VERSION 5.7 ;
  NOWIREEXTENSIONATPIN ON ;
  DIVIDERCHAR "/" ;
  BUSBITCHARS "[]" ;
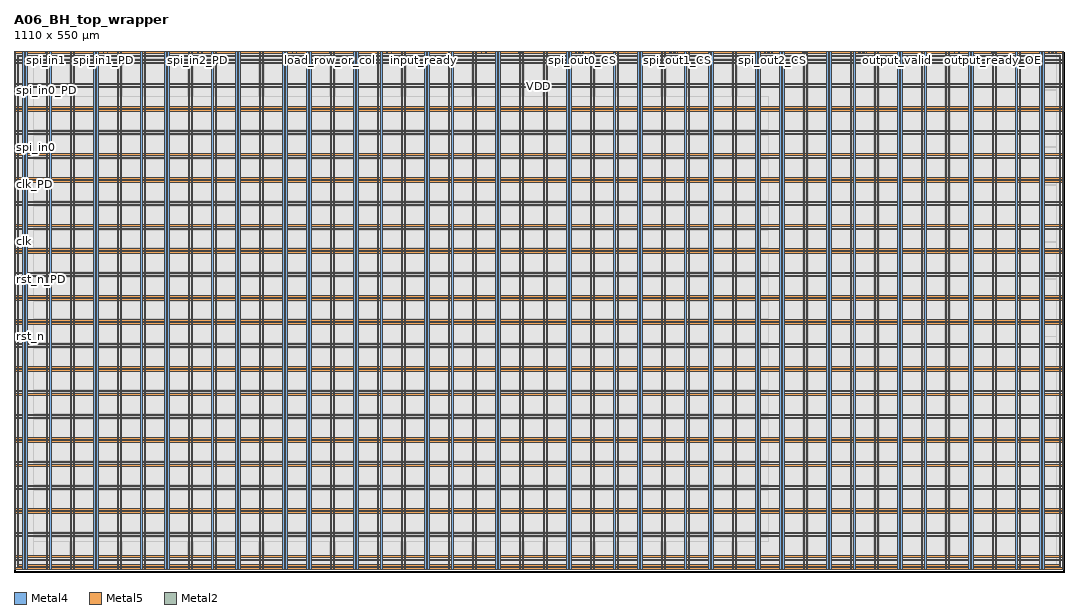
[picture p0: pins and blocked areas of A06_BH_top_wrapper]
MACRO A06_BH_top_wrapper
  CLASS BLOCK ;
  FOREIGN A06_BH_top_wrapper ;
  ORIGIN 0.000 0.000 ;
  SIZE 1110.000 BY 550.000 ;
  PIN VDD
    DIRECTION INOUT ;
    USE POWER ;
    PORT
      LAYER Metal4 ;
        RECT 3.440 6.240 5.040 546.480 ;
    END
    PORT
      LAYER Metal5 ;
        RECT 3.440 6.240 1106.480 7.840 ;
    END
    PORT
      LAYER Metal5 ;
        RECT 3.440 544.880 1106.480 546.480 ;
    END
    PORT
      LAYER Metal4 ;
        RECT 1104.880 6.240 1106.480 546.480 ;
    END
    PORT
      LAYER Metal4 ;
        RECT 9.240 2.940 10.840 549.780 ;
    END
    PORT
      LAYER Metal4 ;
        RECT 34.240 2.940 35.840 549.780 ;
    END
    PORT
      LAYER Metal4 ;
        RECT 59.240 2.940 60.840 549.780 ;
    END
    PORT
      LAYER Metal4 ;
        RECT 84.240 2.940 85.840 549.780 ;
    END
    PORT
      LAYER Metal4 ;
        RECT 109.240 2.940 110.840 549.780 ;
    END
    PORT
      LAYER Metal4 ;
        RECT 134.240 2.940 135.840 549.780 ;
    END
    PORT
      LAYER Metal4 ;
        RECT 159.240 2.940 160.840 549.780 ;
    END
    PORT
      LAYER Metal4 ;
        RECT 184.240 2.940 185.840 549.780 ;
    END
    PORT
      LAYER Metal4 ;
        RECT 209.240 2.940 210.840 549.780 ;
    END
    PORT
      LAYER Metal4 ;
        RECT 234.240 2.940 235.840 549.780 ;
    END
    PORT
      LAYER Metal4 ;
        RECT 259.240 2.940 260.840 549.780 ;
    END
    PORT
      LAYER Metal4 ;
        RECT 284.240 2.940 285.840 549.780 ;
    END
    PORT
      LAYER Metal4 ;
        RECT 309.240 2.940 310.840 549.780 ;
    END
    PORT
      LAYER Metal4 ;
        RECT 334.240 2.940 335.840 549.780 ;
    END
    PORT
      LAYER Metal4 ;
        RECT 359.240 2.940 360.840 549.780 ;
    END
    PORT
      LAYER Metal4 ;
        RECT 384.240 2.940 385.840 549.780 ;
    END
    PORT
      LAYER Metal4 ;
        RECT 409.240 2.940 410.840 549.780 ;
    END
    PORT
      LAYER Metal4 ;
        RECT 434.240 2.940 435.840 549.780 ;
    END
    PORT
      LAYER Metal4 ;
        RECT 459.240 2.940 460.840 549.780 ;
    END
    PORT
      LAYER Metal4 ;
        RECT 484.240 2.940 485.840 549.780 ;
    END
    PORT
      LAYER Metal4 ;
        RECT 509.240 2.940 510.840 549.780 ;
    END
    PORT
      LAYER Metal4 ;
        RECT 534.240 2.940 535.840 549.780 ;
    END
    PORT
      LAYER Metal4 ;
        RECT 559.240 2.940 560.840 549.780 ;
    END
    PORT
      LAYER Metal4 ;
        RECT 584.240 2.940 585.840 549.780 ;
    END
    PORT
      LAYER Metal4 ;
        RECT 609.240 2.940 610.840 549.780 ;
    END
    PORT
      LAYER Metal4 ;
        RECT 634.240 2.940 635.840 549.780 ;
    END
    PORT
      LAYER Metal4 ;
        RECT 659.240 2.940 660.840 549.780 ;
    END
    PORT
      LAYER Metal4 ;
        RECT 684.240 2.940 685.840 549.780 ;
    END
    PORT
      LAYER Metal4 ;
        RECT 709.240 2.940 710.840 549.780 ;
    END
    PORT
      LAYER Metal4 ;
        RECT 734.240 2.940 735.840 549.780 ;
    END
    PORT
      LAYER Metal4 ;
        RECT 759.240 2.940 760.840 549.780 ;
    END
    PORT
      LAYER Metal4 ;
        RECT 784.240 2.940 785.840 549.780 ;
    END
    PORT
      LAYER Metal4 ;
        RECT 809.240 2.940 810.840 549.780 ;
    END
    PORT
      LAYER Metal4 ;
        RECT 834.240 2.940 835.840 549.780 ;
    END
    PORT
      LAYER Metal4 ;
        RECT 859.240 2.940 860.840 549.780 ;
    END
    PORT
      LAYER Metal4 ;
        RECT 884.240 2.940 885.840 549.780 ;
    END
    PORT
      LAYER Metal4 ;
        RECT 909.240 2.940 910.840 549.780 ;
    END
    PORT
      LAYER Metal4 ;
        RECT 934.240 2.940 935.840 549.780 ;
    END
    PORT
      LAYER Metal4 ;
        RECT 959.240 2.940 960.840 549.780 ;
    END
    PORT
      LAYER Metal4 ;
        RECT 984.240 2.940 985.840 549.780 ;
    END
    PORT
      LAYER Metal4 ;
        RECT 1009.240 2.940 1010.840 549.780 ;
    END
    PORT
      LAYER Metal4 ;
        RECT 1034.240 2.940 1035.840 549.780 ;
    END
    PORT
      LAYER Metal4 ;
        RECT 1059.240 2.940 1060.840 549.780 ;
    END
    PORT
      LAYER Metal4 ;
        RECT 1084.240 2.940 1085.840 549.780 ;
    END
    PORT
      LAYER Metal5 ;
        RECT 0.140 12.040 1109.780 13.640 ;
    END
    PORT
      LAYER Metal5 ;
        RECT 0.140 37.040 1109.780 38.640 ;
    END
    PORT
      LAYER Metal5 ;
        RECT 0.140 62.040 1109.780 63.640 ;
    END
    PORT
      LAYER Metal5 ;
        RECT 0.140 87.040 1109.780 88.640 ;
    END
    PORT
      LAYER Metal5 ;
        RECT 0.140 112.040 1109.780 113.640 ;
    END
    PORT
      LAYER Metal5 ;
        RECT 0.140 137.040 1109.780 138.640 ;
    END
    PORT
      LAYER Metal5 ;
        RECT 0.140 162.040 1109.780 163.640 ;
    END
    PORT
      LAYER Metal5 ;
        RECT 0.140 187.040 1109.780 188.640 ;
    END
    PORT
      LAYER Metal5 ;
        RECT 0.140 212.040 1109.780 213.640 ;
    END
    PORT
      LAYER Metal5 ;
        RECT 0.140 237.040 1109.780 238.640 ;
    END
    PORT
      LAYER Metal5 ;
        RECT 0.140 262.040 1109.780 263.640 ;
    END
    PORT
      LAYER Metal5 ;
        RECT 0.140 287.040 1109.780 288.640 ;
    END
    PORT
      LAYER Metal5 ;
        RECT 0.140 312.040 1109.780 313.640 ;
    END
    PORT
      LAYER Metal5 ;
        RECT 0.140 337.040 1109.780 338.640 ;
    END
    PORT
      LAYER Metal5 ;
        RECT 0.140 362.040 1109.780 363.640 ;
    END
    PORT
      LAYER Metal5 ;
        RECT 0.140 387.040 1109.780 388.640 ;
    END
    PORT
      LAYER Metal5 ;
        RECT 0.140 412.040 1109.780 413.640 ;
    END
    PORT
      LAYER Metal5 ;
        RECT 0.140 437.040 1109.780 438.640 ;
    END
    PORT
      LAYER Metal5 ;
        RECT 0.140 462.040 1109.780 463.640 ;
    END
    PORT
      LAYER Metal5 ;
        RECT 0.140 487.040 1109.780 488.640 ;
    END
    PORT
      LAYER Metal5 ;
        RECT 0.140 512.040 1109.780 513.640 ;
    END
    PORT
      LAYER Metal5 ;
        RECT 0.140 537.040 1109.780 538.640 ;
    END
  END VDD
  PIN VSS
    DIRECTION INOUT ;
    USE GROUND ;
    PORT
      LAYER Metal4 ;
        RECT 0.140 2.940 1.740 549.780 ;
    END
    PORT
      LAYER Metal5 ;
        RECT 0.140 2.940 1109.780 4.540 ;
    END
    PORT
      LAYER Metal5 ;
        RECT 0.140 548.180 1109.780 549.780 ;
    END
    PORT
      LAYER Metal4 ;
        RECT 1108.180 2.940 1109.780 549.780 ;
    END
    PORT
      LAYER Metal4 ;
        RECT 12.540 2.940 14.140 549.780 ;
    END
    PORT
      LAYER Metal4 ;
        RECT 37.540 2.940 39.140 549.780 ;
    END
    PORT
      LAYER Metal4 ;
        RECT 62.540 2.940 64.140 549.780 ;
    END
    PORT
      LAYER Metal4 ;
        RECT 87.540 2.940 89.140 549.780 ;
    END
    PORT
      LAYER Metal4 ;
        RECT 112.540 2.940 114.140 549.780 ;
    END
    PORT
      LAYER Metal4 ;
        RECT 137.540 2.940 139.140 549.780 ;
    END
    PORT
      LAYER Metal4 ;
        RECT 162.540 2.940 164.140 549.780 ;
    END
    PORT
      LAYER Metal4 ;
        RECT 187.540 2.940 189.140 549.780 ;
    END
    PORT
      LAYER Metal4 ;
        RECT 212.540 2.940 214.140 549.780 ;
    END
    PORT
      LAYER Metal4 ;
        RECT 237.540 2.940 239.140 549.780 ;
    END
    PORT
      LAYER Metal4 ;
        RECT 262.540 2.940 264.140 549.780 ;
    END
    PORT
      LAYER Metal4 ;
        RECT 287.540 2.940 289.140 549.780 ;
    END
    PORT
      LAYER Metal4 ;
        RECT 312.540 2.940 314.140 549.780 ;
    END
    PORT
      LAYER Metal4 ;
        RECT 337.540 2.940 339.140 549.780 ;
    END
    PORT
      LAYER Metal4 ;
        RECT 362.540 2.940 364.140 549.780 ;
    END
    PORT
      LAYER Metal4 ;
        RECT 387.540 2.940 389.140 549.780 ;
    END
    PORT
      LAYER Metal4 ;
        RECT 412.540 2.940 414.140 549.780 ;
    END
    PORT
      LAYER Metal4 ;
        RECT 437.540 2.940 439.140 549.780 ;
    END
    PORT
      LAYER Metal4 ;
        RECT 462.540 2.940 464.140 549.780 ;
    END
    PORT
      LAYER Metal4 ;
        RECT 487.540 2.940 489.140 549.780 ;
    END
    PORT
      LAYER Metal4 ;
        RECT 512.540 2.940 514.140 549.780 ;
    END
    PORT
      LAYER Metal4 ;
        RECT 537.540 2.940 539.140 549.780 ;
    END
    PORT
      LAYER Metal4 ;
        RECT 562.540 2.940 564.140 549.780 ;
    END
    PORT
      LAYER Metal4 ;
        RECT 587.540 2.940 589.140 549.780 ;
    END
    PORT
      LAYER Metal4 ;
        RECT 612.540 2.940 614.140 549.780 ;
    END
    PORT
      LAYER Metal4 ;
        RECT 637.540 2.940 639.140 549.780 ;
    END
    PORT
      LAYER Metal4 ;
        RECT 662.540 2.940 664.140 549.780 ;
    END
    PORT
      LAYER Metal4 ;
        RECT 687.540 2.940 689.140 549.780 ;
    END
    PORT
      LAYER Metal4 ;
        RECT 712.540 2.940 714.140 549.780 ;
    END
    PORT
      LAYER Metal4 ;
        RECT 737.540 2.940 739.140 549.780 ;
    END
    PORT
      LAYER Metal4 ;
        RECT 762.540 2.940 764.140 549.780 ;
    END
    PORT
      LAYER Metal4 ;
        RECT 787.540 2.940 789.140 549.780 ;
    END
    PORT
      LAYER Metal4 ;
        RECT 812.540 2.940 814.140 549.780 ;
    END
    PORT
      LAYER Metal4 ;
        RECT 837.540 2.940 839.140 549.780 ;
    END
    PORT
      LAYER Metal4 ;
        RECT 862.540 2.940 864.140 549.780 ;
    END
    PORT
      LAYER Metal4 ;
        RECT 887.540 2.940 889.140 549.780 ;
    END
    PORT
      LAYER Metal4 ;
        RECT 912.540 2.940 914.140 549.780 ;
    END
    PORT
      LAYER Metal4 ;
        RECT 937.540 2.940 939.140 549.780 ;
    END
    PORT
      LAYER Metal4 ;
        RECT 962.540 2.940 964.140 549.780 ;
    END
    PORT
      LAYER Metal4 ;
        RECT 987.540 2.940 989.140 549.780 ;
    END
    PORT
      LAYER Metal4 ;
        RECT 1012.540 2.940 1014.140 549.780 ;
    END
    PORT
      LAYER Metal4 ;
        RECT 1037.540 2.940 1039.140 549.780 ;
    END
    PORT
      LAYER Metal4 ;
        RECT 1062.540 2.940 1064.140 549.780 ;
    END
    PORT
      LAYER Metal4 ;
        RECT 1087.540 2.940 1089.140 549.780 ;
    END
    PORT
      LAYER Metal5 ;
        RECT 0.140 15.340 1109.780 16.940 ;
    END
    PORT
      LAYER Metal5 ;
        RECT 0.140 40.340 1109.780 41.940 ;
    END
    PORT
      LAYER Metal5 ;
        RECT 0.140 65.340 1109.780 66.940 ;
    END
    PORT
      LAYER Metal5 ;
        RECT 0.140 90.340 1109.780 91.940 ;
    END
    PORT
      LAYER Metal5 ;
        RECT 0.140 115.340 1109.780 116.940 ;
    END
    PORT
      LAYER Metal5 ;
        RECT 0.140 140.340 1109.780 141.940 ;
    END
    PORT
      LAYER Metal5 ;
        RECT 0.140 165.340 1109.780 166.940 ;
    END
    PORT
      LAYER Metal5 ;
        RECT 0.140 190.340 1109.780 191.940 ;
    END
    PORT
      LAYER Metal5 ;
        RECT 0.140 215.340 1109.780 216.940 ;
    END
    PORT
      LAYER Metal5 ;
        RECT 0.140 240.340 1109.780 241.940 ;
    END
    PORT
      LAYER Metal5 ;
        RECT 0.140 265.340 1109.780 266.940 ;
    END
    PORT
      LAYER Metal5 ;
        RECT 0.140 290.340 1109.780 291.940 ;
    END
    PORT
      LAYER Metal5 ;
        RECT 0.140 315.340 1109.780 316.940 ;
    END
    PORT
      LAYER Metal5 ;
        RECT 0.140 340.340 1109.780 341.940 ;
    END
    PORT
      LAYER Metal5 ;
        RECT 0.140 365.340 1109.780 366.940 ;
    END
    PORT
      LAYER Metal5 ;
        RECT 0.140 390.340 1109.780 391.940 ;
    END
    PORT
      LAYER Metal5 ;
        RECT 0.140 415.340 1109.780 416.940 ;
    END
    PORT
      LAYER Metal5 ;
        RECT 0.140 440.340 1109.780 441.940 ;
    END
    PORT
      LAYER Metal5 ;
        RECT 0.140 465.340 1109.780 466.940 ;
    END
    PORT
      LAYER Metal5 ;
        RECT 0.140 490.340 1109.780 491.940 ;
    END
    PORT
      LAYER Metal5 ;
        RECT 0.140 515.340 1109.780 516.940 ;
    END
    PORT
      LAYER Metal5 ;
        RECT 0.140 540.340 1109.780 541.940 ;
    END
  END VSS
  PIN clk
    DIRECTION INPUT ;
    USE SIGNAL ;
    ANTENNAGATEAREA 4.738000 ;
    PORT
      LAYER Metal2 ;
        RECT 0.000 348.760 1.000 349.140 ;
    END
  END clk
  PIN clk_PD
    DIRECTION OUTPUT TRISTATE ;
    USE SIGNAL ;
    ANTENNADIFFAREA 0.360800 ;
    PORT
      LAYER Metal2 ;
        RECT 0.000 409.290 1.000 409.670 ;
    END
  END clk_PD
  PIN clk_PU
    DIRECTION OUTPUT TRISTATE ;
    USE SIGNAL ;
    ANTENNADIFFAREA 0.360800 ;
    PORT
      LAYER Metal2 ;
        RECT 0.000 413.655 1.000 414.035 ;
    END
  END clk_PU
  PIN input_ready
    DIRECTION INPUT ;
    USE SIGNAL ;
    ANTENNAGATEAREA 1.183000 ;
    PORT
      LAYER Metal2 ;
        RECT 433.760 549.000 434.140 550.000 ;
    END
  END input_ready
  PIN input_ready_PD
    DIRECTION OUTPUT TRISTATE ;
    USE SIGNAL ;
    ANTENNADIFFAREA 0.360800 ;
    PORT
      LAYER Metal2 ;
        RECT 494.290 549.000 494.670 550.000 ;
    END
  END input_ready_PD
  PIN input_ready_PU
    DIRECTION OUTPUT TRISTATE ;
    USE SIGNAL ;
    ANTENNADIFFAREA 0.360800 ;
    PORT
      LAYER Metal2 ;
        RECT 498.655 549.000 499.035 550.000 ;
    END
  END input_ready_PU
  PIN load_row_or_col
    DIRECTION INPUT ;
    USE SIGNAL ;
    ANTENNAGATEAREA 2.204000 ;
    PORT
      LAYER Metal2 ;
        RECT 333.760 549.000 334.140 550.000 ;
    END
  END load_row_or_col
  PIN load_row_or_col_PD
    DIRECTION OUTPUT TRISTATE ;
    USE SIGNAL ;
    ANTENNADIFFAREA 0.360800 ;
    PORT
      LAYER Metal2 ;
        RECT 394.290 549.000 394.670 550.000 ;
    END
  END load_row_or_col_PD
  PIN load_row_or_col_PU
    DIRECTION OUTPUT TRISTATE ;
    USE SIGNAL ;
    ANTENNADIFFAREA 0.360800 ;
    PORT
      LAYER Metal2 ;
        RECT 398.655 549.000 399.035 550.000 ;
    END
  END load_row_or_col_PU
  PIN output_ready_CS
    DIRECTION OUTPUT TRISTATE ;
    USE SIGNAL ;
    ANTENNADIFFAREA 0.360800 ;
    PORT
      LAYER Metal2 ;
        RECT 1101.260 549.000 1101.640 550.000 ;
    END
  END output_ready_CS
  PIN output_ready_IE
    DIRECTION OUTPUT TRISTATE ;
    USE SIGNAL ;
    ANTENNADIFFAREA 0.360800 ;
    PORT
      LAYER Metal2 ;
        RECT 1093.235 549.000 1093.615 550.000 ;
    END
  END output_ready_IE
  PIN output_ready_IN
    DIRECTION INPUT ;
    USE SIGNAL ;
    PORT
      LAYER Metal2 ;
        RECT 1033.760 549.000 1034.140 550.000 ;
    END
  END output_ready_IN
  PIN output_ready_OE
    DIRECTION OUTPUT TRISTATE ;
    USE SIGNAL ;
    ANTENNADIFFAREA 0.536800 ;
    PORT
      LAYER Metal2 ;
        RECT 1034.490 549.000 1034.870 550.000 ;
    END
  END output_ready_OE
  PIN output_ready_OUT
    DIRECTION OUTPUT TRISTATE ;
    USE SIGNAL ;
    ANTENNADIFFAREA 1.986000 ;
    PORT
      LAYER Metal2 ;
        RECT 1035.220 549.000 1035.600 550.000 ;
    END
  END output_ready_OUT
  PIN output_ready_PD
    DIRECTION OUTPUT TRISTATE ;
    USE SIGNAL ;
    ANTENNADIFFAREA 0.360800 ;
    PORT
      LAYER Metal2 ;
        RECT 1094.290 549.000 1094.670 550.000 ;
    END
  END output_ready_PD
  PIN output_ready_PDRV0
    DIRECTION OUTPUT TRISTATE ;
    USE SIGNAL ;
    ANTENNADIFFAREA 0.360800 ;
    PORT
      LAYER Metal2 ;
        RECT 1097.510 549.000 1097.890 550.000 ;
    END
  END output_ready_PDRV0
  PIN output_ready_PDRV1
    DIRECTION OUTPUT TRISTATE ;
    USE SIGNAL ;
    ANTENNADIFFAREA 0.360800 ;
    PORT
      LAYER Metal2 ;
        RECT 1096.800 549.000 1097.180 550.000 ;
    END
  END output_ready_PDRV1
  PIN output_ready_PU
    DIRECTION OUTPUT TRISTATE ;
    USE SIGNAL ;
    ANTENNADIFFAREA 0.360800 ;
    PORT
      LAYER Metal2 ;
        RECT 1098.655 549.000 1099.035 550.000 ;
    END
  END output_ready_PU
  PIN output_ready_SL
    DIRECTION OUTPUT TRISTATE ;
    USE SIGNAL ;
    ANTENNADIFFAREA 0.360800 ;
    PORT
      LAYER Metal2 ;
        RECT 1035.950 549.000 1036.330 550.000 ;
    END
  END output_ready_SL
  PIN output_valid
    DIRECTION INPUT ;
    USE SIGNAL ;
    ANTENNAGATEAREA 0.498500 ;
    PORT
      LAYER Metal2 ;
        RECT 933.760 549.000 934.140 550.000 ;
    END
  END output_valid
  PIN output_valid_PD
    DIRECTION OUTPUT TRISTATE ;
    USE SIGNAL ;
    ANTENNADIFFAREA 0.360800 ;
    PORT
      LAYER Metal2 ;
        RECT 994.290 549.000 994.670 550.000 ;
    END
  END output_valid_PD
  PIN output_valid_PU
    DIRECTION OUTPUT TRISTATE ;
    USE SIGNAL ;
    ANTENNADIFFAREA 0.360800 ;
    PORT
      LAYER Metal2 ;
        RECT 998.655 549.000 999.035 550.000 ;
    END
  END output_valid_PU
  PIN rst_n
    DIRECTION INPUT ;
    USE SIGNAL ;
    ANTENNAGATEAREA 0.726000 ;
    PORT
      LAYER Metal2 ;
        RECT 0.000 248.760 1.000 249.140 ;
    END
  END rst_n
  PIN rst_n_PD
    DIRECTION OUTPUT TRISTATE ;
    USE SIGNAL ;
    ANTENNADIFFAREA 0.360800 ;
    PORT
      LAYER Metal2 ;
        RECT 0.000 309.290 1.000 309.670 ;
    END
  END rst_n_PD
  PIN rst_n_PU
    DIRECTION OUTPUT TRISTATE ;
    USE SIGNAL ;
    ANTENNADIFFAREA 0.360800 ;
    PORT
      LAYER Metal2 ;
        RECT 0.000 313.655 1.000 314.035 ;
    END
  END rst_n_PU
  PIN spi_in0
    DIRECTION INPUT ;
    USE SIGNAL ;
    ANTENNAGATEAREA 2.204000 ;
    PORT
      LAYER Metal2 ;
        RECT 0.000 448.760 1.000 449.140 ;
    END
  END spi_in0
  PIN spi_in0_PD
    DIRECTION OUTPUT TRISTATE ;
    USE SIGNAL ;
    ANTENNADIFFAREA 0.360800 ;
    PORT
      LAYER Metal2 ;
        RECT 0.000 509.290 1.000 509.670 ;
    END
  END spi_in0_PD
  PIN spi_in0_PU
    DIRECTION OUTPUT TRISTATE ;
    USE SIGNAL ;
    ANTENNADIFFAREA 0.360800 ;
    PORT
      LAYER Metal2 ;
        RECT 0.000 513.655 1.000 514.035 ;
    END
  END spi_in0_PU
  PIN spi_in1
    DIRECTION INPUT ;
    USE SIGNAL ;
    ANTENNAGATEAREA 2.369000 ;
    PORT
      LAYER Metal2 ;
        RECT 33.760 549.000 34.140 550.000 ;
    END
  END spi_in1
  PIN spi_in1_PD
    DIRECTION OUTPUT TRISTATE ;
    USE SIGNAL ;
    ANTENNADIFFAREA 0.360800 ;
    PORT
      LAYER Metal2 ;
        RECT 94.290 549.000 94.670 550.000 ;
    END
  END spi_in1_PD
  PIN spi_in1_PU
    DIRECTION OUTPUT TRISTATE ;
    USE SIGNAL ;
    ANTENNADIFFAREA 0.360800 ;
    PORT
      LAYER Metal2 ;
        RECT 98.655 549.000 99.035 550.000 ;
    END
  END spi_in1_PU
  PIN spi_in2
    DIRECTION INPUT ;
    USE SIGNAL ;
    ANTENNAGATEAREA 2.369000 ;
    PORT
      LAYER Metal2 ;
        RECT 133.760 549.000 134.140 550.000 ;
    END
  END spi_in2
  PIN spi_in2_PD
    DIRECTION OUTPUT TRISTATE ;
    USE SIGNAL ;
    ANTENNADIFFAREA 0.360800 ;
    PORT
      LAYER Metal2 ;
        RECT 194.290 549.000 194.670 550.000 ;
    END
  END spi_in2_PD
  PIN spi_in2_PU
    DIRECTION OUTPUT TRISTATE ;
    USE SIGNAL ;
    ANTENNADIFFAREA 0.360800 ;
    PORT
      LAYER Metal2 ;
        RECT 198.655 549.000 199.035 550.000 ;
    END
  END spi_in2_PU
  PIN spi_in3
    DIRECTION INPUT ;
    USE SIGNAL ;
    ANTENNAGATEAREA 2.369000 ;
    PORT
      LAYER Metal2 ;
        RECT 233.760 549.000 234.140 550.000 ;
    END
  END spi_in3
  PIN spi_in3_PD
    DIRECTION OUTPUT TRISTATE ;
    USE SIGNAL ;
    ANTENNADIFFAREA 0.360800 ;
    PORT
      LAYER Metal2 ;
        RECT 294.290 549.000 294.670 550.000 ;
    END
  END spi_in3_PD
  PIN spi_in3_PU
    DIRECTION OUTPUT TRISTATE ;
    USE SIGNAL ;
    ANTENNADIFFAREA 0.360800 ;
    PORT
      LAYER Metal2 ;
        RECT 298.655 549.000 299.035 550.000 ;
    END
  END spi_in3_PU
  PIN spi_out0_CS
    DIRECTION OUTPUT TRISTATE ;
    USE SIGNAL ;
    ANTENNADIFFAREA 0.360800 ;
    PORT
      LAYER Metal2 ;
        RECT 601.260 549.000 601.640 550.000 ;
    END
  END spi_out0_CS
  PIN spi_out0_IE
    DIRECTION OUTPUT TRISTATE ;
    USE SIGNAL ;
    ANTENNADIFFAREA 0.360800 ;
    PORT
      LAYER Metal2 ;
        RECT 593.235 549.000 593.615 550.000 ;
    END
  END spi_out0_IE
  PIN spi_out0_IN
    DIRECTION INPUT ;
    USE SIGNAL ;
    PORT
      LAYER Metal2 ;
        RECT 533.760 549.000 534.140 550.000 ;
    END
  END spi_out0_IN
  PIN spi_out0_OE
    DIRECTION OUTPUT TRISTATE ;
    USE SIGNAL ;
    ANTENNADIFFAREA 0.536800 ;
    PORT
      LAYER Metal2 ;
        RECT 534.490 549.000 534.870 550.000 ;
    END
  END spi_out0_OE
  PIN spi_out0_OUT
    DIRECTION OUTPUT TRISTATE ;
    USE SIGNAL ;
    ANTENNADIFFAREA 2.080400 ;
    PORT
      LAYER Metal2 ;
        RECT 535.220 549.000 535.600 550.000 ;
    END
  END spi_out0_OUT
  PIN spi_out0_PD
    DIRECTION OUTPUT TRISTATE ;
    USE SIGNAL ;
    ANTENNADIFFAREA 0.360800 ;
    PORT
      LAYER Metal2 ;
        RECT 594.290 549.000 594.670 550.000 ;
    END
  END spi_out0_PD
  PIN spi_out0_PDRV0
    DIRECTION OUTPUT TRISTATE ;
    USE SIGNAL ;
    ANTENNADIFFAREA 0.360800 ;
    PORT
      LAYER Metal2 ;
        RECT 597.510 549.000 597.890 550.000 ;
    END
  END spi_out0_PDRV0
  PIN spi_out0_PDRV1
    DIRECTION OUTPUT TRISTATE ;
    USE SIGNAL ;
    ANTENNADIFFAREA 0.360800 ;
    PORT
      LAYER Metal2 ;
        RECT 596.800 549.000 597.180 550.000 ;
    END
  END spi_out0_PDRV1
  PIN spi_out0_PU
    DIRECTION OUTPUT TRISTATE ;
    USE SIGNAL ;
    ANTENNADIFFAREA 0.360800 ;
    PORT
      LAYER Metal2 ;
        RECT 598.655 549.000 599.035 550.000 ;
    END
  END spi_out0_PU
  PIN spi_out0_SL
    DIRECTION OUTPUT TRISTATE ;
    USE SIGNAL ;
    ANTENNADIFFAREA 0.360800 ;
    PORT
      LAYER Metal2 ;
        RECT 535.950 549.000 536.330 550.000 ;
    END
  END spi_out0_SL
  PIN spi_out1_CS
    DIRECTION OUTPUT TRISTATE ;
    USE SIGNAL ;
    ANTENNADIFFAREA 0.360800 ;
    PORT
      LAYER Metal2 ;
        RECT 701.260 549.000 701.640 550.000 ;
    END
  END spi_out1_CS
  PIN spi_out1_IE
    DIRECTION OUTPUT TRISTATE ;
    USE SIGNAL ;
    ANTENNADIFFAREA 0.360800 ;
    PORT
      LAYER Metal2 ;
        RECT 693.235 549.000 693.615 550.000 ;
    END
  END spi_out1_IE
  PIN spi_out1_IN
    DIRECTION INPUT ;
    USE SIGNAL ;
    PORT
      LAYER Metal2 ;
        RECT 633.760 549.000 634.140 550.000 ;
    END
  END spi_out1_IN
  PIN spi_out1_OE
    DIRECTION OUTPUT TRISTATE ;
    USE SIGNAL ;
    ANTENNADIFFAREA 0.536800 ;
    PORT
      LAYER Metal2 ;
        RECT 634.490 549.000 634.870 550.000 ;
    END
  END spi_out1_OE
  PIN spi_out1_OUT
    DIRECTION OUTPUT TRISTATE ;
    USE SIGNAL ;
    ANTENNADIFFAREA 2.080400 ;
    PORT
      LAYER Metal2 ;
        RECT 635.220 549.000 635.600 550.000 ;
    END
  END spi_out1_OUT
  PIN spi_out1_PD
    DIRECTION OUTPUT TRISTATE ;
    USE SIGNAL ;
    ANTENNADIFFAREA 0.360800 ;
    PORT
      LAYER Metal2 ;
        RECT 694.290 549.000 694.670 550.000 ;
    END
  END spi_out1_PD
  PIN spi_out1_PDRV0
    DIRECTION OUTPUT TRISTATE ;
    USE SIGNAL ;
    ANTENNADIFFAREA 0.360800 ;
    PORT
      LAYER Metal2 ;
        RECT 697.510 549.000 697.890 550.000 ;
    END
  END spi_out1_PDRV0
  PIN spi_out1_PDRV1
    DIRECTION OUTPUT TRISTATE ;
    USE SIGNAL ;
    ANTENNADIFFAREA 0.360800 ;
    PORT
      LAYER Metal2 ;
        RECT 696.800 549.000 697.180 550.000 ;
    END
  END spi_out1_PDRV1
  PIN spi_out1_PU
    DIRECTION OUTPUT TRISTATE ;
    USE SIGNAL ;
    ANTENNADIFFAREA 0.360800 ;
    PORT
      LAYER Metal2 ;
        RECT 698.655 549.000 699.035 550.000 ;
    END
  END spi_out1_PU
  PIN spi_out1_SL
    DIRECTION OUTPUT TRISTATE ;
    USE SIGNAL ;
    ANTENNADIFFAREA 0.360800 ;
    PORT
      LAYER Metal2 ;
        RECT 635.950 549.000 636.330 550.000 ;
    END
  END spi_out1_SL
  PIN spi_out2_CS
    DIRECTION OUTPUT TRISTATE ;
    USE SIGNAL ;
    ANTENNADIFFAREA 0.360800 ;
    PORT
      LAYER Metal2 ;
        RECT 801.260 549.000 801.640 550.000 ;
    END
  END spi_out2_CS
  PIN spi_out2_IE
    DIRECTION OUTPUT TRISTATE ;
    USE SIGNAL ;
    ANTENNADIFFAREA 0.360800 ;
    PORT
      LAYER Metal2 ;
        RECT 793.235 549.000 793.615 550.000 ;
    END
  END spi_out2_IE
  PIN spi_out2_IN
    DIRECTION INPUT ;
    USE SIGNAL ;
    PORT
      LAYER Metal2 ;
        RECT 733.760 549.000 734.140 550.000 ;
    END
  END spi_out2_IN
  PIN spi_out2_OE
    DIRECTION OUTPUT TRISTATE ;
    USE SIGNAL ;
    ANTENNADIFFAREA 0.536800 ;
    PORT
      LAYER Metal2 ;
        RECT 734.490 549.000 734.870 550.000 ;
    END
  END spi_out2_OE
  PIN spi_out2_OUT
    DIRECTION OUTPUT TRISTATE ;
    USE SIGNAL ;
    ANTENNADIFFAREA 2.080400 ;
    PORT
      LAYER Metal2 ;
        RECT 735.220 549.000 735.600 550.000 ;
    END
  END spi_out2_OUT
  PIN spi_out2_PD
    DIRECTION OUTPUT TRISTATE ;
    USE SIGNAL ;
    ANTENNADIFFAREA 0.360800 ;
    PORT
      LAYER Metal2 ;
        RECT 794.290 549.000 794.670 550.000 ;
    END
  END spi_out2_PD
  PIN spi_out2_PDRV0
    DIRECTION OUTPUT TRISTATE ;
    USE SIGNAL ;
    ANTENNADIFFAREA 0.360800 ;
    PORT
      LAYER Metal2 ;
        RECT 797.510 549.000 797.890 550.000 ;
    END
  END spi_out2_PDRV0
  PIN spi_out2_PDRV1
    DIRECTION OUTPUT TRISTATE ;
    USE SIGNAL ;
    ANTENNADIFFAREA 0.360800 ;
    PORT
      LAYER Metal2 ;
        RECT 796.800 549.000 797.180 550.000 ;
    END
  END spi_out2_PDRV1
  PIN spi_out2_PU
    DIRECTION OUTPUT TRISTATE ;
    USE SIGNAL ;
    ANTENNADIFFAREA 0.360800 ;
    PORT
      LAYER Metal2 ;
        RECT 798.655 549.000 799.035 550.000 ;
    END
  END spi_out2_PU
  PIN spi_out2_SL
    DIRECTION OUTPUT TRISTATE ;
    USE SIGNAL ;
    ANTENNADIFFAREA 0.360800 ;
    PORT
      LAYER Metal2 ;
        RECT 735.950 549.000 736.330 550.000 ;
    END
  END spi_out2_SL
  PIN spi_out3_CS
    DIRECTION OUTPUT TRISTATE ;
    USE SIGNAL ;
    ANTENNADIFFAREA 0.360800 ;
    PORT
      LAYER Metal2 ;
        RECT 901.260 549.000 901.640 550.000 ;
    END
  END spi_out3_CS
  PIN spi_out3_IE
    DIRECTION OUTPUT TRISTATE ;
    USE SIGNAL ;
    ANTENNADIFFAREA 0.360800 ;
    PORT
      LAYER Metal2 ;
        RECT 893.235 549.000 893.615 550.000 ;
    END
  END spi_out3_IE
  PIN spi_out3_IN
    DIRECTION INPUT ;
    USE SIGNAL ;
    PORT
      LAYER Metal2 ;
        RECT 833.760 549.000 834.140 550.000 ;
    END
  END spi_out3_IN
  PIN spi_out3_OE
    DIRECTION OUTPUT TRISTATE ;
    USE SIGNAL ;
    ANTENNADIFFAREA 0.536800 ;
    PORT
      LAYER Metal2 ;
        RECT 834.490 549.000 834.870 550.000 ;
    END
  END spi_out3_OE
  PIN spi_out3_OUT
    DIRECTION OUTPUT TRISTATE ;
    USE SIGNAL ;
    ANTENNADIFFAREA 2.080400 ;
    PORT
      LAYER Metal2 ;
        RECT 835.220 549.000 835.600 550.000 ;
    END
  END spi_out3_OUT
  PIN spi_out3_PD
    DIRECTION OUTPUT TRISTATE ;
    USE SIGNAL ;
    ANTENNADIFFAREA 0.360800 ;
    PORT
      LAYER Metal2 ;
        RECT 894.290 549.000 894.670 550.000 ;
    END
  END spi_out3_PD
  PIN spi_out3_PDRV0
    DIRECTION OUTPUT TRISTATE ;
    USE SIGNAL ;
    ANTENNADIFFAREA 0.360800 ;
    PORT
      LAYER Metal2 ;
        RECT 897.510 549.000 897.890 550.000 ;
    END
  END spi_out3_PDRV0
  PIN spi_out3_PDRV1
    DIRECTION OUTPUT TRISTATE ;
    USE SIGNAL ;
    ANTENNADIFFAREA 0.360800 ;
    PORT
      LAYER Metal2 ;
        RECT 896.800 549.000 897.180 550.000 ;
    END
  END spi_out3_PDRV1
  PIN spi_out3_PU
    DIRECTION OUTPUT TRISTATE ;
    USE SIGNAL ;
    ANTENNADIFFAREA 0.360800 ;
    PORT
      LAYER Metal2 ;
        RECT 898.655 549.000 899.035 550.000 ;
    END
  END spi_out3_PU
  PIN spi_out3_SL
    DIRECTION OUTPUT TRISTATE ;
    USE SIGNAL ;
    ANTENNADIFFAREA 0.360800 ;
    PORT
      LAYER Metal2 ;
        RECT 835.950 549.000 836.330 550.000 ;
    END
  END spi_out3_SL
  OBS
      LAYER Metal1 ;
        RECT 4.330 7.540 1104.880 548.650 ;
      LAYER Metal2 ;
        RECT 0.000 548.700 33.460 549.220 ;
        RECT 34.440 548.700 93.990 549.220 ;
        RECT 94.970 548.700 98.355 549.220 ;
        RECT 99.335 548.700 133.460 549.220 ;
        RECT 134.440 548.700 193.990 549.220 ;
        RECT 194.970 548.700 198.355 549.220 ;
        RECT 199.335 548.700 233.460 549.220 ;
        RECT 234.440 548.700 293.990 549.220 ;
        RECT 294.970 548.700 298.355 549.220 ;
        RECT 299.335 548.700 333.460 549.220 ;
        RECT 334.440 548.700 393.990 549.220 ;
        RECT 394.970 548.700 398.355 549.220 ;
        RECT 399.335 548.700 433.460 549.220 ;
        RECT 434.440 548.700 493.990 549.220 ;
        RECT 494.970 548.700 498.355 549.220 ;
        RECT 499.335 548.700 533.460 549.220 ;
        RECT 536.630 548.700 592.935 549.220 ;
        RECT 593.915 548.700 593.990 549.220 ;
        RECT 594.970 548.700 596.500 549.220 ;
        RECT 598.190 548.700 598.355 549.220 ;
        RECT 599.335 548.700 600.960 549.220 ;
        RECT 601.940 548.700 633.460 549.220 ;
        RECT 636.630 548.700 692.935 549.220 ;
        RECT 693.915 548.700 693.990 549.220 ;
        RECT 694.970 548.700 696.500 549.220 ;
        RECT 698.190 548.700 698.355 549.220 ;
        RECT 699.335 548.700 700.960 549.220 ;
        RECT 701.940 548.700 733.460 549.220 ;
        RECT 736.630 548.700 792.935 549.220 ;
        RECT 793.915 548.700 793.990 549.220 ;
        RECT 794.970 548.700 796.500 549.220 ;
        RECT 798.190 548.700 798.355 549.220 ;
        RECT 799.335 548.700 800.960 549.220 ;
        RECT 801.940 548.700 833.460 549.220 ;
        RECT 836.630 548.700 892.935 549.220 ;
        RECT 893.915 548.700 893.990 549.220 ;
        RECT 894.970 548.700 896.500 549.220 ;
        RECT 898.190 548.700 898.355 549.220 ;
        RECT 899.335 548.700 900.960 549.220 ;
        RECT 901.940 548.700 933.460 549.220 ;
        RECT 934.440 548.700 993.990 549.220 ;
        RECT 994.970 548.700 998.355 549.220 ;
        RECT 999.335 548.700 1033.460 549.220 ;
        RECT 1036.630 548.700 1092.935 549.220 ;
        RECT 1093.915 548.700 1093.990 549.220 ;
        RECT 1094.970 548.700 1096.500 549.220 ;
        RECT 1098.190 548.700 1098.355 549.220 ;
        RECT 1099.335 548.700 1100.960 549.220 ;
        RECT 1101.940 548.700 1102.500 549.220 ;
        RECT 0.000 514.335 1102.500 548.700 ;
        RECT 1.300 513.355 1102.500 514.335 ;
        RECT 0.000 509.970 1102.500 513.355 ;
        RECT 1.300 508.990 1102.500 509.970 ;
        RECT 0.000 449.440 1102.500 508.990 ;
        RECT 1.300 448.460 1102.500 449.440 ;
        RECT 0.000 414.335 1102.500 448.460 ;
        RECT 1.300 413.355 1102.500 414.335 ;
        RECT 0.000 409.970 1102.500 413.355 ;
        RECT 1.300 408.990 1102.500 409.970 ;
        RECT 0.000 349.440 1102.500 408.990 ;
        RECT 1.300 348.460 1102.500 349.440 ;
        RECT 0.000 314.335 1102.500 348.460 ;
        RECT 1.300 313.355 1102.500 314.335 ;
        RECT 0.000 309.970 1102.500 313.355 ;
        RECT 1.300 308.990 1102.500 309.970 ;
        RECT 0.000 249.440 1102.500 308.990 ;
        RECT 1.300 248.460 1102.500 249.440 ;
        RECT 0.000 7.650 1102.500 248.460 ;
      LAYER Metal3 ;
        RECT 0.230 7.700 1089.050 546.420 ;
      LAYER Metal4 ;
        RECT 20.860 15.210 33.940 542.550 ;
        RECT 36.140 15.210 37.240 542.550 ;
        RECT 39.440 15.210 58.940 542.550 ;
        RECT 61.140 15.210 62.240 542.550 ;
        RECT 64.440 15.210 83.940 542.550 ;
        RECT 86.140 15.210 87.240 542.550 ;
        RECT 89.440 15.210 108.940 542.550 ;
        RECT 111.140 15.210 112.240 542.550 ;
        RECT 114.440 15.210 133.940 542.550 ;
        RECT 136.140 15.210 137.240 542.550 ;
        RECT 139.440 15.210 158.940 542.550 ;
        RECT 161.140 15.210 162.240 542.550 ;
        RECT 164.440 15.210 183.940 542.550 ;
        RECT 186.140 15.210 187.240 542.550 ;
        RECT 189.440 15.210 208.940 542.550 ;
        RECT 211.140 15.210 212.240 542.550 ;
        RECT 214.440 15.210 233.940 542.550 ;
        RECT 236.140 15.210 237.240 542.550 ;
        RECT 239.440 15.210 258.940 542.550 ;
        RECT 261.140 15.210 262.240 542.550 ;
        RECT 264.440 15.210 283.940 542.550 ;
        RECT 286.140 15.210 287.240 542.550 ;
        RECT 289.440 15.210 308.940 542.550 ;
        RECT 311.140 15.210 312.240 542.550 ;
        RECT 314.440 15.210 333.940 542.550 ;
        RECT 336.140 15.210 337.240 542.550 ;
        RECT 339.440 15.210 358.940 542.550 ;
        RECT 361.140 15.210 362.240 542.550 ;
        RECT 364.440 15.210 383.940 542.550 ;
        RECT 386.140 15.210 387.240 542.550 ;
        RECT 389.440 15.210 408.940 542.550 ;
        RECT 411.140 15.210 412.240 542.550 ;
        RECT 414.440 15.210 433.940 542.550 ;
        RECT 436.140 15.210 437.240 542.550 ;
        RECT 439.440 15.210 458.940 542.550 ;
        RECT 461.140 15.210 462.240 542.550 ;
        RECT 464.440 15.210 483.940 542.550 ;
        RECT 486.140 15.210 487.240 542.550 ;
        RECT 489.440 15.210 508.940 542.550 ;
        RECT 511.140 15.210 512.240 542.550 ;
        RECT 514.440 15.210 533.940 542.550 ;
        RECT 536.140 15.210 537.240 542.550 ;
        RECT 539.440 15.210 558.940 542.550 ;
        RECT 561.140 15.210 562.240 542.550 ;
        RECT 564.440 15.210 583.940 542.550 ;
        RECT 586.140 15.210 587.240 542.550 ;
        RECT 589.440 15.210 608.940 542.550 ;
        RECT 611.140 15.210 612.240 542.550 ;
        RECT 614.440 15.210 633.940 542.550 ;
        RECT 636.140 15.210 637.240 542.550 ;
        RECT 639.440 15.210 658.940 542.550 ;
        RECT 661.140 15.210 662.240 542.550 ;
        RECT 664.440 15.210 683.940 542.550 ;
        RECT 686.140 15.210 687.240 542.550 ;
        RECT 689.440 15.210 708.940 542.550 ;
        RECT 711.140 15.210 712.240 542.550 ;
        RECT 714.440 15.210 733.940 542.550 ;
        RECT 736.140 15.210 737.240 542.550 ;
        RECT 739.440 15.210 758.940 542.550 ;
        RECT 761.140 15.210 762.240 542.550 ;
        RECT 764.440 15.210 783.940 542.550 ;
        RECT 786.140 15.210 787.240 542.550 ;
        RECT 789.440 15.210 808.940 542.550 ;
        RECT 811.140 15.210 812.240 542.550 ;
        RECT 814.440 15.210 833.940 542.550 ;
        RECT 836.140 15.210 837.240 542.550 ;
        RECT 839.440 15.210 858.940 542.550 ;
        RECT 861.140 15.210 862.240 542.550 ;
        RECT 864.440 15.210 883.940 542.550 ;
        RECT 886.140 15.210 887.240 542.550 ;
        RECT 889.440 15.210 908.940 542.550 ;
        RECT 911.140 15.210 912.240 542.550 ;
        RECT 914.440 15.210 933.940 542.550 ;
        RECT 936.140 15.210 937.240 542.550 ;
        RECT 939.440 15.210 958.940 542.550 ;
        RECT 961.140 15.210 962.240 542.550 ;
        RECT 964.440 15.210 983.940 542.550 ;
        RECT 986.140 15.210 987.240 542.550 ;
        RECT 989.440 15.210 989.940 542.550 ;
      LAYER Metal5 ;
        RECT 20.780 492.540 797.940 502.870 ;
        RECT 20.780 489.240 797.940 489.740 ;
        RECT 20.780 467.540 797.940 486.440 ;
        RECT 20.780 464.240 797.940 464.740 ;
        RECT 20.780 442.540 797.940 461.440 ;
        RECT 20.780 439.240 797.940 439.740 ;
        RECT 20.780 417.540 797.940 436.440 ;
        RECT 20.780 414.240 797.940 414.740 ;
        RECT 20.780 392.540 797.940 411.440 ;
        RECT 20.780 389.240 797.940 389.740 ;
        RECT 20.780 367.540 797.940 386.440 ;
        RECT 20.780 364.240 797.940 364.740 ;
        RECT 20.780 342.540 797.940 361.440 ;
        RECT 20.780 339.240 797.940 339.740 ;
        RECT 20.780 317.540 797.940 336.440 ;
        RECT 20.780 314.240 797.940 314.740 ;
        RECT 20.780 292.540 797.940 311.440 ;
        RECT 20.780 289.240 797.940 289.740 ;
        RECT 20.780 267.540 797.940 286.440 ;
        RECT 20.780 264.240 797.940 264.740 ;
        RECT 20.780 242.540 797.940 261.440 ;
        RECT 20.780 239.240 797.940 239.740 ;
        RECT 20.780 217.540 797.940 236.440 ;
        RECT 20.780 214.240 797.940 214.740 ;
        RECT 20.780 192.540 797.940 211.440 ;
        RECT 20.780 189.240 797.940 189.740 ;
        RECT 20.780 167.540 797.940 186.440 ;
        RECT 20.780 164.240 797.940 164.740 ;
        RECT 20.780 142.540 797.940 161.440 ;
        RECT 20.780 139.240 797.940 139.740 ;
        RECT 20.780 117.540 797.940 136.440 ;
        RECT 20.780 114.240 797.940 114.740 ;
        RECT 20.780 92.540 797.940 111.440 ;
        RECT 20.780 89.240 797.940 89.740 ;
        RECT 20.780 67.540 797.940 86.440 ;
        RECT 20.780 64.240 797.940 64.740 ;
        RECT 20.780 42.540 797.940 61.440 ;
        RECT 20.780 39.240 797.940 39.740 ;
        RECT 20.780 32.630 797.940 36.440 ;
  END
END A06_BH_top_wrapper
END LIBRARY

